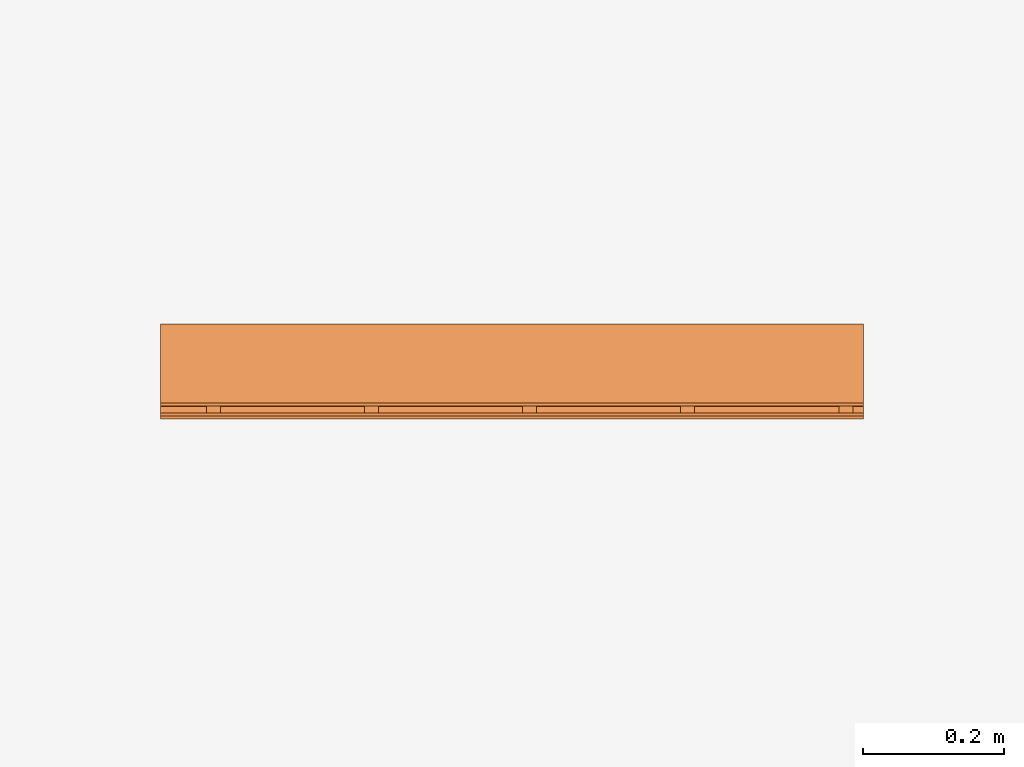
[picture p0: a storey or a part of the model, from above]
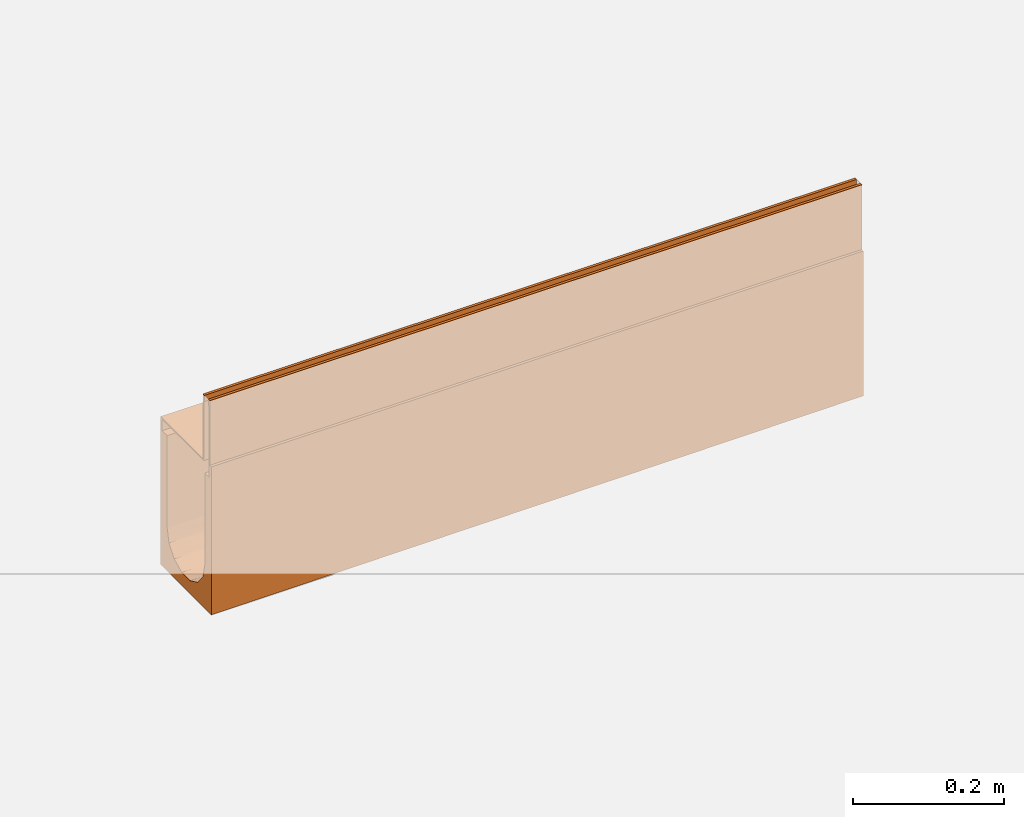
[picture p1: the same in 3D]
Properties of the parts of a building model (IFC2X3)

# File
Description: ViewDefinition [CoordinationView]
File name: 23018 - No 18 Sloping Channel - 1000mm LG - Invert Depth 215-220mm.ifc
Time: 2013-10-31T17:29:08
Written by: Autodesk Revit 2013
Made in: 20120221_2030(x64)

# IfcProject, Project Number
LongName: Project Name; Phase: Project Status

# IfcSite, Default
RefLatitude: 42, 21, 30, 344238; RefLongitude: -71, -3, -35, -194702; RefElevation: 0 mm

# IfcBuilding
Pset_BuildingCommon - NumberOfStoreys: 1
Other - Project Number: Project Number; Client Name: Owner; Project Issue Date: Issue Date; Project Address: ## Street City, State Zip; Project Name: Project Name; Project Status: Project Status

# IfcBuildingStorey, Level 1
LongName: Level 1; Elevation: 0 mm
Constraints - Elevation Base: 0; Elevation: 0 mm
Graphics - Symbol at End 2 Default: yes; Symbol at End 1 Default: no; Color: 0; Line Weight: 1; Symbol: M_Level Head - Circle: M_Level Head - Circle; Line Pattern: Center
Identity Data - Name: Level 1; Building Story: yes; Structural: no
Dimensions - Computation Height: 0 mm

# IfcBuildingElementProxy: 23018 - No 18 Sloping Channel - 1000mm LG - Invert Depth 215/220mm, Civil-Drainage-Channel-ACO-MultiDrain-M100D-Brickslot-Channel-System:23018 - No 18 Sloping Channel - 1000mm LG - Invert Depth 215/220mm:23018 - No 18 Sloping Channel - 1000mm LG - Invert Depth 215/220mm:196059
In: Level 1
Material: Steel, Galvanized, Vienite® Synthetic Resin Concrete
Constraints - Moves With Nearby Elements: no; Level: Level: Level 1
Construction - 23465_Load Class D400_Brickslot Grating_Galvanized Steel_1000mm Long: yes; 23467_Load Class D400_Brickslot Access Unit_Galvanised Steel_500mm Long: no; 23404_Universal Endcap (Female End): no; 23404_Universal Endcap (Male End): no; 23462_Load Class C250_Brickslot Access Unit_Galvanised Steel_500mm Long: no; 23466_Load Class D400_Brickslot Grating_Galvanized Steel_500mm Long: no; 23461_Load Class C250_Brickslot Grating_Galvanized Steel_500mm Long: no; 23460_Load Class C250_Brickslot Grating_Galvanized Steel_1000mm Long: no; Shallow Depth Channel with seal: no; Shallow Depth Channel: no; 23410_Sump Unit: no; Constant Depth Channel: no; Sloping Channel: yes; Constant Depth Junction Channel: no
Dimensions - Volume: 11651158 mm3; Brickslot Void Length: 1000 mm; Custom_Void_length: 0 mm; Brickslot Void Depth: 0 mm; FloorCut_Length: -1000 mm; EndCap Position: 1000 mm; Length: 1000 mm; Brickslot Access Unit Void Bottom Depth: -6605 mm; Brickslot Access Unit Void Depth: -6500 mm; SlopingInvertDepth: 165 mm; Depth: 150 mm; SlopingOverallDepth: 235 mm; Floor Cut Gap: 105 mm; ShallowOverallDepth: 75 mm; SlopingEndOverallDepth: 240 mm; EndCap_Height: 240 mm; Brickslot Access Unit Floor Cut Length: 500 mm; GratingLength: -1000 mm; InvDepth: 80 mm; Length Drain: -1000 mm; ShallowInvDepth: 55 mm; FloorCut_Depth: 240 mm; Access_Custom_Void_Length: 0 mm; SlopingEndInvertDepth: 170 mm; FloorCut_Width: 135 mm
Phasing - Phase Created: New Construction
Pset_BuildingElementProxyCommon - Reference: 23018 - No 18 Sloping Channel - 1000mm LG - Invert Depth 215/220mm
Identity Data - Watermarked With: BIM Manager Premium Suite; Watermark 2: This file is water marked and users are prohibited to reproduce, adapt, distribute this information; Model: ACO MultiDrain MD Brickslot- M100D; e-mail Technical: technical@aco.co.uk; e-mail Sales: customersupport@aco.co.uk; Cost: 0; Product Code: 23018; Watermark 1: This file is the property of ACO Technologies PLC; Manufacturer: ACO Technologies plc - ACO Water Management Division; Telephone: +44 (0)1462 816666; Fax: +44 (0)1462 815895; OmniClass Number: 23.70.50.24; Maintenance guidelines: http://www.aco.co.uk/download.php?id=173; Assembly Code: D2040; URL: www.aco.co.uk; OmniClass Title: Rainwater Removal; Address: ACO Business Park, Hitchin Road, Shefford, Bedfordshire, United Kingdom SG17 5TE; Product Page URL: http://www.aco.co.uk/product_detail.php?id=58; Type Comments: ACO MultiDrain M100D No 18 Sloping Channel 1000mm Long; Assembly Description: Rain Water Drainage; Product brochure: http://www.aco.co.uk/download.php?id=173; Price: POA - contact ACO; Installation guidelines: http://www.aco.co.uk/download.php?id=173; Model Description: Channel drainage system
Other - Watermarked By: www.aco.co.uk; Created By: www.aco.co.uk; Revision: 1
Green Building Properties - Channel Recyclable: Fully recyclable; Channel Recycled Material Content: 20% minimum; Edge Rail Recyclable: Fully recyclable; Edge Rail Recycled Material Content: Between 40% - 90%
General - TagNumber: 0; SerialNumber: 0
Model Properties - End Cap Product code 23404: No 306 Universal End Cap - 135mm wide x 300mm long - Spigot Ø110mm x 50mm long - Silver - Polypropylene - 0.16kg; Brickslot Grating Product code 23465: Load Class D400 - Brickslot Galvanised Steel - 1000mm long x 105mm high - 10mm Slot - Intake area - 10000mm²/m - 6.6 Kg; Brickslot Access Unit Product code 23462: Load Class C250 - Brickslot Access Unit Galvanised Steel - 500mm long x 105mm high - 10mm Slot - Intake area - 10000mm²/m - 6.4 Kg; Brickslot Grating Product code 23466: Load Class D400 - Brickslot Galvanised Steel - 500mm long x 105mm high - 10mm Slot - Intake area - 10000mm²/m - 3.3 Kg; Brickslot Access Unit Product code 23467: Load Class D400 - Brickslot Access Unit Galvanised Steel - 500mm long x 105mm high - 10mm Slot - Intake area - 10000mm²/m - 6.4 Kg; Brickslot Grating Product code 23460: Load Class C250 - Brickslot Galvanised Steel - 1000mm long x 105mm high - 10mm Slot - Intake area - 10000mm²/m - 6.6 Kg; Brickslot Grating Product code 23461: Load Class C250 - Brickslot Galvanised Steel - 500mm long x 105mm high - 10mm Slot - Intake area - 10000mm²/m -3.3 Kg
Data - Product Weight: 18.6 Kg; Load Class: A 15 - D 400; ACO Hydraulic Design Software: http://www.acodesign.co.uk; Pre-formed Outlet Ø: N/A; Concrete Surround Volume - Load Class D 400 - Concrete Pavement: N/A; Product Dimensions: 1000mm x 135mm x 235mm/240mm (LxWxH); Installation - Concrete Grade: Refer to brochure; Product Standard: BS EN 1433:2002, CE marked; Invert Depth: 215mm/220mm /220 215mm/220mm; Hydraulic Performance: http://www.aco.co.uk/download.php?id=173; Concrete Surround Volume - Load Class B 125 - C 250 - Concrete Pavement: N/A; Concrete Surround Volume - Load Class A 15 - Concrete Pavement: N/A; Channel C.S.A: N/A
Materials and Finishes - Edge Rail Material: Steel; Channel Material: Vienite® Synthetic Resin Concrete; Edge Rail Colour: Silver; Channel Colour: Brown; Edge Rail Finish: Pre-galvanised

# IfcOpeningElement: Recess (2)
In: Level 1
Dimensions - Volume: 24965710000 mm3; Perimeter: 20000 mm; Area: 25000000 mm2; Thickness: 1000 mm
Structural - Enable Analytical Model: no; Structural: no
Constraints - Height Offset From Level: 0 mm; Related to Mass: no; Room Bounding: yes; Level: Level: Level 1
Phasing - Phase Created: New Construction
Analytical Properties - Absorptance: 0.1; Heat Transfer Coefficient (U): 0.837; Roughness: 1; Thermal mass: 1359800; Thermal Resistance (R): 1.19474
Materials and Finishes - Structural Material: Earth
Construction - Function: 0; Default Thickness: 1000 mm
Graphics - Coarse Scale Fill Color: 0

# IfcSlab: Floor:Generic Floor - 1000mm, Floor:Generic Floor - 1000mm:193825
In: Level 1
PredefinedType: FLOOR; Material: Earth 1000 mm
Dimensions - Volume: 24965710000 mm3; Perimeter: 20000 mm; Area: 25000000 mm2; Thickness: 1000 mm
Structural - Enable Analytical Model: no; Structural: no
Constraints - Height Offset From Level: 0 mm; Related to Mass: no; Room Bounding: yes; Level: Level: Level 1
Phasing - Phase Created: New Construction
Pset_SlabCommon - Reference: Generic Floor - 1000mm; IsExternal: no; LoadBearing: yes
Analytical Properties - Absorptance: 0.1; Heat Transfer Coefficient (U): 0.837; Roughness: 1; Thermal mass: 1359800; Thermal Resistance (R): 1.19474
Materials and Finishes - Structural Material: Earth
Construction - Function: 0; Default Thickness: 1000 mm
Graphics - Coarse Scale Fill Color: 0
